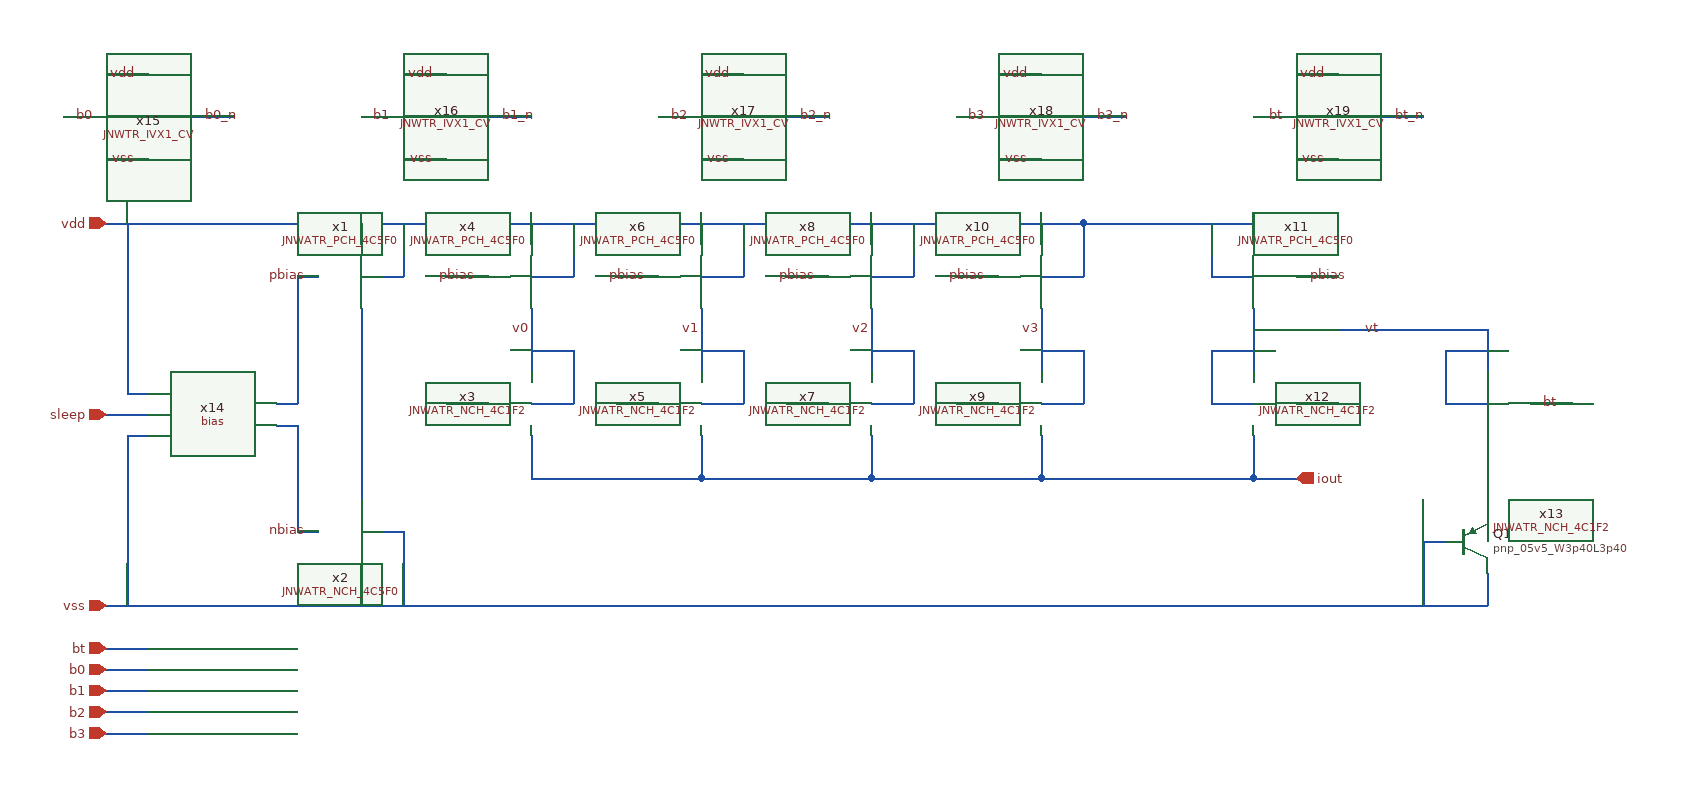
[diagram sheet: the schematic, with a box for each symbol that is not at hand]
v {xschem version=3.4.6 file_version=1.2}
G {}
K {}
V {}
S {}
E {}
N 640 500 640 520 {lab=vdd}
N 720 550 760 550 {lab=pbias}
N 800 500 800 520 {lab=vdd}
N 800 580 800 640 {lab=v0}
N 800 700 800 740 {lab=iout}
N 720 670 760 670 {lab=b0_n}
N 800 550 840 550 {lab=vdd}
N 840 500 840 550 {lab=vdd}
N 800 670 840 670 {lab=v0}
N 840 620 840 670 {lab=v0}
N 800 620 840 620 {lab=v0}
N 800 740 960 740 {lab=iout}
N 880 550 920 550 {lab=pbias}
N 960 500 960 520 {lab=vdd}
N 960 580 960 640 {lab=v1}
N 960 700 960 740 {lab=iout}
N 880 670 920 670 {lab=b1_n}
N 960 550 1000 550 {lab=vdd}
N 1000 500 1000 550 {lab=vdd}
N 960 670 1000 670 {lab=v1}
N 1000 620 1000 670 {lab=v1}
N 960 620 1000 620 {lab=v1}
N 960 740 1120 740 {lab=iout}
N 1040 550 1080 550 {lab=pbias}
N 1120 500 1120 520 {lab=vdd}
N 1120 580 1120 640 {lab=v2}
N 1120 700 1120 740 {lab=iout}
N 1040 670 1080 670 {lab=b2_n}
N 1120 550 1160 550 {lab=vdd}
N 1160 500 1160 550 {lab=vdd}
N 1120 670 1160 670 {lab=v2}
N 1160 620 1160 670 {lab=v2}
N 1120 620 1160 620 {lab=v2}
N 1120 740 1280 740 {lab=iout}
N 1200 550 1240 550 {lab=pbias}
N 1280 500 1280 520 {lab=vdd}
N 1280 580 1280 640 {lab=v0}
N 1280 700 1280 740 {lab=iout}
N 1200 670 1240 670 {lab=b3_n}
N 1280 550 1320 550 {lab=vdd}
N 1320 500 1320 550 {lab=vdd}
N 1280 670 1320 670 {lab=v0}
N 1320 620 1320 670 {lab=v0}
N 1280 620 1320 620 {lab=v0}
N 400 500 1320 500 {lab=vdd}
N 1280 740 1480 740 {lab=iout}
N 400 860 1040 860 {lab=vss}
N 360 400 400 400 {lab=b0}
N 400 940 440 940 {lab=b1}
N 400 960 440 960 {lab=b2}
N 400 980 440 980 {lab=b3}
N 400 900 440 900 {lab=bt}
N 400 360 440 360 {lab=vdd}
N 400 440 440 440 {lab=vss}
N 480 400 520 400 {lab=b0_n}
N 640 400 680 400 {lab=b1}
N 680 360 720 360 {lab=vdd}
N 680 440 720 440 {lab=vss}
N 760 400 800 400 {lab=b1_n}
N 920 400 960 400 {lab=b2}
N 960 360 1000 360 {lab=vdd}
N 960 440 1000 440 {lab=vss}
N 1040 400 1080 400 {lab=b2_n}
N 1200 400 1240 400 {lab=b3}
N 1240 360 1280 360 {lab=vdd}
N 1240 440 1280 440 {lab=vss}
N 1320 400 1360 400 {lab=b3_n}
N 1480 400 1520 400 {lab=bt}
N 1520 360 1560 360 {lab=vdd}
N 1520 440 1560 440 {lab=vss}
N 1600 400 1640 400 {lab=bt_n}
N 400 920 440 920 {lab=b0}
N 640 550 680 550 {lab=vdd}
N 680 500 680 550 {lab=vdd}
N 640 580 640 760 {lab=#net1}
N 640 790 680 790 {lab=vss}
N 680 790 680 860 {lab=vss}
N 640 820 640 860 {lab=vss}
N 400 680 440 680 {lab=sleep}
N 420 500 420 660 {lab=vdd}
N 420 700 420 860 {lab=vss}
N 580 690 580 790 {lab=nbias}
N 580 790 600 790 {lab=nbias}
N 580 550 580 670 {lab=pbias}
N 580 550 600 550 {lab=pbias}
N 560 690 580 690 {lab=nbias}
N 560 670 580 670 {lab=pbias}
N 420 700 440 700 {lab=vss}
N 420 660 440 660 {lab=vdd}
N 1040 860 1700 860 {lab=vss}
N 1320 500 1480 500 {lab=vdd}
N 1700 700 1700 770 {lab=#net2}
N 1700 830 1700 860 {lab=vss}
N 1640 800 1660 800 {lab=vss}
N 1640 800 1640 860 {lab=vss}
N 1520 550 1560 550 {lab=pbias}
N 1480 500 1480 520 {lab=vdd}
N 1480 580 1480 640 {lab=#net3}
N 1480 700 1480 740 {lab=iout}
N 1520 670 1560 670 {lab=bt_n}
N 1440 550 1480 550 {lab=vdd}
N 1440 500 1440 550 {lab=vdd}
N 1440 670 1480 670 {lab=#net3}
N 1440 620 1440 670 {lab=#net3}
N 1440 620 1480 620 {lab=#net3}
N 1480 600 1700 600 {lab=#net3}
N 1700 600 1700 640 {lab=#net3}
N 1660 670 1700 670 {lab=#net3}
N 1660 620 1660 670 {lab=#net3}
N 1660 620 1700 620 {lab=#net3}
N 1740 670 1780 670 {lab=bt}
N 1480 740 1520 740 {lab=iout}
C {JNW_ATR_SKY130A/JNWATR_PCH_4C5F0.sym} 600 550 0 0 {name=x1 }
C {JNW_ATR_SKY130A/JNWATR_PCH_4C5F0.sym} 760 550 0 0 {name=x4 }
C {JNW_ATR_SKY130A/JNWATR_PCH_4C5F0.sym} 920 550 0 0 {name=x6 }
C {JNW_ATR_SKY130A/JNWATR_PCH_4C5F0.sym} 1080 550 0 0 {name=x8 }
C {JNW_ATR_SKY130A/JNWATR_PCH_4C5F0.sym} 1240 550 0 0 {name=x10 }
C {devices/lab_wire.sym} 1230 670 0 0 {name=p3 sig_type=std_logic lab=b3_n
}
C {devices/lab_wire.sym} 1070 670 0 0 {name=p4 sig_type=std_logic lab=b2_n
}
C {devices/lab_wire.sym} 910 670 0 0 {name=p5 sig_type=std_logic lab=b1_n
}
C {devices/lab_wire.sym} 750 670 0 0 {name=p6 sig_type=std_logic lab=b0_n
}
C {devices/ipin.sym} 400 500 0 0 {name=p14 lab=vdd}
C {devices/ipin.sym} 400 860 0 0 {name=p15 lab=vss}
C {devices/ipin.sym} 400 940 0 0 {name=p17 lab=b1}
C {devices/ipin.sym} 400 960 0 0 {name=p18 lab=b2}
C {devices/ipin.sym} 400 980 0 0 {name=p19 lab=b3}
C {devices/ipin.sym} 400 900 0 0 {name=p20 lab=bt}
C {JNW_TR_SKY130A/JNWTR_IVX1_CV.sym} 400 400 0 0 {name=x15 }
C {devices/lab_wire.sym} 430 440 2 1 {name=p23 sig_type=std_logic lab=vss}
C {devices/lab_wire.sym} 430 360 0 0 {name=p24 sig_type=std_logic lab=vdd}
C {JNW_TR_SKY130A/JNWTR_IVX1_CV.sym} 680 400 0 0 {name=x16 }
C {devices/lab_wire.sym} 710 440 2 1 {name=p26 sig_type=std_logic lab=vss}
C {devices/lab_wire.sym} 710 360 0 0 {name=p27 sig_type=std_logic lab=vdd}
C {JNW_TR_SKY130A/JNWTR_IVX1_CV.sym} 960 400 0 0 {name=x17 }
C {devices/lab_wire.sym} 990 440 2 1 {name=p30 sig_type=std_logic lab=vss}
C {devices/lab_wire.sym} 990 360 0 0 {name=p31 sig_type=std_logic lab=vdd}
C {JNW_TR_SKY130A/JNWTR_IVX1_CV.sym} 1240 400 0 0 {name=x18 }
C {devices/lab_wire.sym} 1270 440 2 1 {name=p34 sig_type=std_logic lab=vss}
C {devices/lab_wire.sym} 1270 360 0 0 {name=p35 sig_type=std_logic lab=vdd}
C {JNW_TR_SKY130A/JNWTR_IVX1_CV.sym} 1520 400 0 0 {name=x19 }
C {devices/lab_wire.sym} 1550 440 2 1 {name=p38 sig_type=std_logic lab=vss}
C {devices/lab_wire.sym} 1550 360 0 0 {name=p39 sig_type=std_logic lab=vdd}
C {devices/lab_wire.sym} 390 400 0 0 {name=p16 sig_type=std_logic lab=b0}
C {devices/lab_wire.sym} 1230 400 0 0 {name=p25 sig_type=std_logic lab=b3}
C {devices/lab_wire.sym} 670 400 0 0 {name=p28 sig_type=std_logic lab=b1}
C {devices/lab_wire.sym} 1510 400 0 0 {name=p29 sig_type=std_logic lab=bt}
C {devices/lab_wire.sym} 950 400 0 0 {name=p32 sig_type=std_logic lab=b2}
C {devices/ipin.sym} 400 920 0 0 {name=p7 lab=b0}
C {devices/lab_wire.sym} 1330 400 0 1 {name=p36 sig_type=std_logic lab=b3_n}
C {devices/lab_wire.sym} 490 400 0 1 {name=p37 sig_type=std_logic lab=b0_n}
C {devices/lab_wire.sym} 770 400 0 1 {name=p40 sig_type=std_logic lab=b1_n}
C {devices/lab_wire.sym} 1610 400 0 1 {name=p41 sig_type=std_logic lab=bt_n}
C {devices/lab_wire.sym} 1050 400 0 1 {name=p45 sig_type=std_logic lab=b2_n}
C {devices/lab_wire.sym} 910 550 0 0 {name=p9 sig_type=std_logic lab=pbias
}
C {devices/lab_wire.sym} 1070 550 0 0 {name=p8 sig_type=std_logic lab=pbias
}
C {devices/lab_wire.sym} 1230 550 0 0 {name=p10 sig_type=std_logic lab=pbias
}
C {JNW_ATR_SKY130A/JNWATR_NCH_4C5F0.sym} 600 790 0 0 {name=x2}
C {devices/lab_wire.sym} 750 550 0 0 {name=p12 sig_type=std_logic lab=pbias
}
C {LELO_TORD_SKY130A/bias.sym} 500 680 0 0 {name=x14}
C {devices/ipin.sym} 400 680 0 0 {name=p33 lab=sleep}
C {devices/lab_wire.sym} 590 550 0 0 {name=p13 sig_type=std_logic lab=pbias
}
C {devices/lab_wire.sym} 590 790 2 1 {name=p21 sig_type=std_logic lab=nbias
}
C {JNW_ATR_SKY130A/JNWATR_NCH_4C1F2.sym} 760 670 0 0 {name=x3 }
C {JNW_ATR_SKY130A/JNWATR_NCH_4C1F2.sym} 920 670 0 0 {name=x5 }
C {JNW_ATR_SKY130A/JNWATR_NCH_4C1F2.sym} 1080 670 0 0 {name=x7 }
C {JNW_ATR_SKY130A/JNWATR_NCH_4C1F2.sym} 1240 670 0 0 {name=x9 }
C {sky130_fd_pr/pnp_05v5.sym} 1680 800 0 0 {name=Q1
model=pnp_05v5_W3p40L3p40
m=1
spiceprefix=X
}
C {JNW_ATR_SKY130A/JNWATR_PCH_4C5F0.sym} 1520 550 0 1 {name=x11 }
C {devices/lab_wire.sym} 1530 670 0 1 {name=p1 sig_type=std_logic lab=bt_n
}
C {devices/lab_wire.sym} 1530 550 0 1 {name=p2 sig_type=std_logic lab=pbias
}
C {JNW_ATR_SKY130A/JNWATR_NCH_4C1F2.sym} 1520 670 0 1 {name=x12 }
C {JNW_ATR_SKY130A/JNWATR_NCH_4C1F2.sym} 1740 670 0 1 {name=x13 }
C {devices/lab_wire.sym} 1750 670 0 1 {name=p11 sig_type=std_logic lab=bt
}
C {devices/opin.sym} 1520 740 0 0 {name=p22 lab=iout}
C {devices/lab_wire.sym} 800 600 2 1 {name=p66 sig_type=std_logic lab=v0
}
C {devices/lab_wire.sym} 960 600 2 1 {name=p42 sig_type=std_logic lab=v1
}
C {devices/lab_wire.sym} 1120 600 2 1 {name=p43 sig_type=std_logic lab=v2
}
C {devices/lab_wire.sym} 1280 600 2 1 {name=p44 sig_type=std_logic lab=v3
}
C {devices/lab_wire.sym} 1600 600 2 1 {name=p46 sig_type=std_logic lab=vt
}
